One B-rep face of a CAD part: STEP entity #152825.
In plain terms, the planar face has unit normal (0, 0, 1).
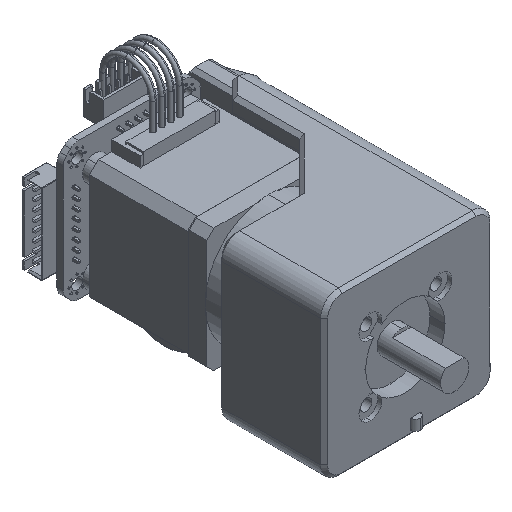
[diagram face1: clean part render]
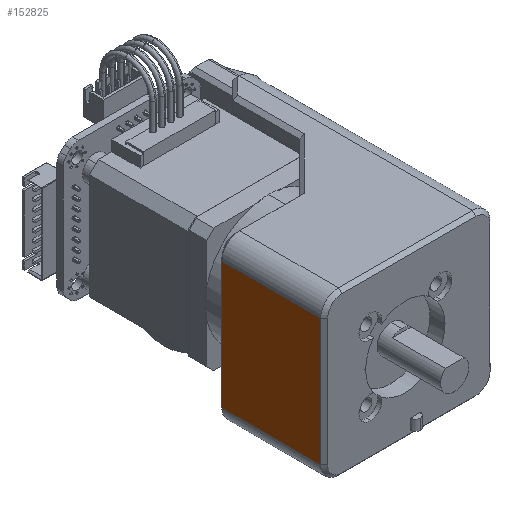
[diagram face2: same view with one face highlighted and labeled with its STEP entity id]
Its self-contained STEP definition (entity closure, numbers rounded to 3 decimals):
#148390 = PLANE('',#148391);
#148391 = AXIS2_PLACEMENT_3D('',#148392,#148393,#148394);
#148392 = CARTESIAN_POINT('',(95.,0.,72.5));
#148393 = DIRECTION('',(0.707,0.,0.707
    ));
#148394 = DIRECTION('',(0.,-1.,0.));
#152021 = CYLINDRICAL_SURFACE('',#152022,5.);
#152022 = AXIS2_PLACEMENT_3D('',#152023,#152024,#152025);
#152023 = CARTESIAN_POINT('',(0.,65.631,67.5));
#152024 = DIRECTION('',(1.,0.,0.));
#152025 = DIRECTION('',(0.,0.,-1.));
#152446 = CYLINDRICAL_SURFACE('',#152447,5.);
#152447 = AXIS2_PLACEMENT_3D('',#152448,#152449,#152450);
#152448 = CARTESIAN_POINT('',(0.,29.631,67.5));
#152449 = DIRECTION('',(1.,0.,0.));
#152450 = DIRECTION('',(0.,0.,-1.));
#152756 = PLANE('',#152757);
#152757 = AXIS2_PLACEMENT_3D('',#152758,#152759,#152760);
#152758 = CARTESIAN_POINT('',(67.,0.,72.5));
#152759 = DIRECTION('',(-0.707,-0.,0.707));
#152760 = DIRECTION('',(-0.,1.,0.));
#152825 = ADVANCED_FACE('',(#152826),#152840,.T.);
#152826 = FACE_BOUND('',#152827,.T.);
#152827 = EDGE_LOOP('',(#152828,#152858,#152881,#152904));
#152828 = ORIENTED_EDGE('',*,*,#152829,.T.);
#152829 = EDGE_CURVE('',#152830,#152832,#152834,.T.);
#152830 = VERTEX_POINT('',#152831);
#152831 = CARTESIAN_POINT('',(95.,65.631,72.5));
#152832 = VERTEX_POINT('',#152833);
#152833 = CARTESIAN_POINT('',(67.,65.631,72.5));
#152834 = SURFACE_CURVE('',#152835,(#152839,#152851),.PCURVE_S1.);
#152835 = LINE('',#152836,#152837);
#152836 = CARTESIAN_POINT('',(66.,65.631,72.5));
#152837 = VECTOR('',#152838,1.);
#152838 = DIRECTION('',(-1.,0.,0.));
#152839 = PCURVE('',#152840,#152845);
#152840 = PLANE('',#152841);
#152841 = AXIS2_PLACEMENT_3D('',#152842,#152843,#152844);
#152842 = CARTESIAN_POINT('',(0.,0.,72.5));
#152843 = DIRECTION('',(0.,-0.,1.));
#152844 = DIRECTION('',(1.,0.,0.));
#152845 = DEFINITIONAL_REPRESENTATION('',(#152846),#152850);
#152846 = LINE('',#152847,#152848);
#152847 = CARTESIAN_POINT('',(66.,65.631));
#152848 = VECTOR('',#152849,1.);
#152849 = DIRECTION('',(-1.,0.));
#152850 = ( GEOMETRIC_REPRESENTATION_CONTEXT(2) 
PARAMETRIC_REPRESENTATION_CONTEXT() REPRESENTATION_CONTEXT('2D SPACE',''
  ) );
#152851 = PCURVE('',#152021,#152852);
#152852 = DEFINITIONAL_REPRESENTATION('',(#152853),#152857);
#152853 = LINE('',#152854,#152855);
#152854 = CARTESIAN_POINT('',(3.142,66.));
#152855 = VECTOR('',#152856,1.);
#152856 = DIRECTION('',(0.,-1.));
#152857 = ( GEOMETRIC_REPRESENTATION_CONTEXT(2) 
PARAMETRIC_REPRESENTATION_CONTEXT() REPRESENTATION_CONTEXT('2D SPACE',''
  ) );
#152858 = ORIENTED_EDGE('',*,*,#152859,.T.);
#152859 = EDGE_CURVE('',#152832,#152860,#152862,.T.);
#152860 = VERTEX_POINT('',#152861);
#152861 = CARTESIAN_POINT('',(67.,29.631,72.5));
#152862 = SURFACE_CURVE('',#152863,(#152867,#152874),.PCURVE_S1.);
#152863 = LINE('',#152864,#152865);
#152864 = CARTESIAN_POINT('',(67.,29.631,72.5));
#152865 = VECTOR('',#152866,1.);
#152866 = DIRECTION('',(0.,-1.,0.));
#152867 = PCURVE('',#152840,#152868);
#152868 = DEFINITIONAL_REPRESENTATION('',(#152869),#152873);
#152869 = LINE('',#152870,#152871);
#152870 = CARTESIAN_POINT('',(67.,29.631));
#152871 = VECTOR('',#152872,1.);
#152872 = DIRECTION('',(0.,-1.));
#152873 = ( GEOMETRIC_REPRESENTATION_CONTEXT(2) 
PARAMETRIC_REPRESENTATION_CONTEXT() REPRESENTATION_CONTEXT('2D SPACE',''
  ) );
#152874 = PCURVE('',#152756,#152875);
#152875 = DEFINITIONAL_REPRESENTATION('',(#152876),#152880);
#152876 = LINE('',#152877,#152878);
#152877 = CARTESIAN_POINT('',(29.631,0.));
#152878 = VECTOR('',#152879,1.);
#152879 = DIRECTION('',(-1.,-0.));
#152880 = ( GEOMETRIC_REPRESENTATION_CONTEXT(2) 
PARAMETRIC_REPRESENTATION_CONTEXT() REPRESENTATION_CONTEXT('2D SPACE',''
  ) );
#152881 = ORIENTED_EDGE('',*,*,#152882,.T.);
#152882 = EDGE_CURVE('',#152860,#152883,#152885,.T.);
#152883 = VERTEX_POINT('',#152884);
#152884 = CARTESIAN_POINT('',(95.,29.631,72.5));
#152885 = SURFACE_CURVE('',#152886,(#152890,#152897),.PCURVE_S1.);
#152886 = LINE('',#152887,#152888);
#152887 = CARTESIAN_POINT('',(0.,29.631,72.5));
#152888 = VECTOR('',#152889,1.);
#152889 = DIRECTION('',(1.,0.,0.));
#152890 = PCURVE('',#152840,#152891);
#152891 = DEFINITIONAL_REPRESENTATION('',(#152892),#152896);
#152892 = LINE('',#152893,#152894);
#152893 = CARTESIAN_POINT('',(0.,29.631));
#152894 = VECTOR('',#152895,1.);
#152895 = DIRECTION('',(1.,0.));
#152896 = ( GEOMETRIC_REPRESENTATION_CONTEXT(2) 
PARAMETRIC_REPRESENTATION_CONTEXT() REPRESENTATION_CONTEXT('2D SPACE',''
  ) );
#152897 = PCURVE('',#152446,#152898);
#152898 = DEFINITIONAL_REPRESENTATION('',(#152899),#152903);
#152899 = LINE('',#152900,#152901);
#152900 = CARTESIAN_POINT('',(3.142,0.));
#152901 = VECTOR('',#152902,1.);
#152902 = DIRECTION('',(0.,1.));
#152903 = ( GEOMETRIC_REPRESENTATION_CONTEXT(2) 
PARAMETRIC_REPRESENTATION_CONTEXT() REPRESENTATION_CONTEXT('2D SPACE',''
  ) );
#152904 = ORIENTED_EDGE('',*,*,#152905,.T.);
#152905 = EDGE_CURVE('',#152883,#152830,#152906,.T.);
#152906 = SURFACE_CURVE('',#152907,(#152911,#152918),.PCURVE_S1.);
#152907 = LINE('',#152908,#152909);
#152908 = CARTESIAN_POINT('',(95.,65.631,72.5));
#152909 = VECTOR('',#152910,1.);
#152910 = DIRECTION('',(0.,1.,0.));
#152911 = PCURVE('',#152840,#152912);
#152912 = DEFINITIONAL_REPRESENTATION('',(#152913),#152917);
#152913 = LINE('',#152914,#152915);
#152914 = CARTESIAN_POINT('',(95.,65.631));
#152915 = VECTOR('',#152916,1.);
#152916 = DIRECTION('',(0.,1.));
#152917 = ( GEOMETRIC_REPRESENTATION_CONTEXT(2) 
PARAMETRIC_REPRESENTATION_CONTEXT() REPRESENTATION_CONTEXT('2D SPACE',''
  ) );
#152918 = PCURVE('',#148390,#152919);
#152919 = DEFINITIONAL_REPRESENTATION('',(#152920),#152924);
#152920 = LINE('',#152921,#152922);
#152921 = CARTESIAN_POINT('',(-65.631,0.));
#152922 = VECTOR('',#152923,1.);
#152923 = DIRECTION('',(-1.,0.));
#152924 = ( GEOMETRIC_REPRESENTATION_CONTEXT(2) 
PARAMETRIC_REPRESENTATION_CONTEXT() REPRESENTATION_CONTEXT('2D SPACE',''
  ) );
